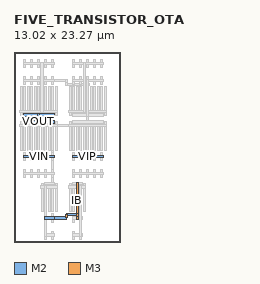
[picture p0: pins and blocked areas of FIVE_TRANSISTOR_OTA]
MACRO FIVE_TRANSISTOR_OTA
  ORIGIN 0 0 ;
  FOREIGN FIVE_TRANSISTOR_OTA 0 0 ;
  SIZE 13.02 BY 23.27 ;
  PIN IB
    DIRECTION INOUT ;
    USE SIGNAL ;
    PORT 
      LAYER M2 ;
        RECT 3.7 2.8 4.9 3.08 ;
      LAYER M3 ;
        RECT 7.6 2.78 7.88 7.3 ;
      LAYER M2 ;
        RECT 4.73 2.8 6.45 3.08 ;
      LAYER M3 ;
        RECT 6.31 2.94 6.59 3.36 ;
      LAYER M2 ;
        RECT 6.45 3.22 7.74 3.5 ;
      LAYER M3 ;
        RECT 7.6 3.175 7.88 3.545 ;
    END
  END IB
  PIN VOUT
    DIRECTION INOUT ;
    USE SIGNAL ;
    PORT 
      LAYER M2 ;
        RECT 1.12 14.56 4.9 14.84 ;
      LAYER M2 ;
        RECT 1.12 15.4 4.9 15.68 ;
      LAYER M2 ;
        RECT 2.85 14.56 3.17 14.84 ;
      LAYER M3 ;
        RECT 2.87 14.7 3.15 15.54 ;
      LAYER M2 ;
        RECT 2.85 15.4 3.17 15.68 ;
    END
  END VOUT
  PIN VIP
    DIRECTION INOUT ;
    USE SIGNAL ;
    PORT 
      LAYER M2 ;
        RECT 7.14 10.36 10.92 10.64 ;
    END
  END VIP
  PIN VIN
    DIRECTION INOUT ;
    USE SIGNAL ;
    PORT 
      LAYER M2 ;
        RECT 1.12 10.36 4.9 10.64 ;
    END
  END VIN
  OBS 
  LAYER M2 ;
        RECT 1.12 19.6 4.9 19.88 ;
  LAYER M3 ;
        RECT 8.89 15.38 9.17 19.9 ;
  LAYER M2 ;
        RECT 7.14 14.56 10.92 14.84 ;
  LAYER M2 ;
        RECT 4.73 19.6 6.45 19.88 ;
  LAYER M3 ;
        RECT 6.31 19.32 6.59 19.74 ;
  LAYER M2 ;
        RECT 6.45 19.18 9.03 19.46 ;
  LAYER M3 ;
        RECT 8.89 19.135 9.17 19.505 ;
  LAYER M3 ;
        RECT 8.89 14.7 9.17 15.54 ;
  LAYER M2 ;
        RECT 8.87 14.56 9.19 14.84 ;
  LAYER M2 ;
        RECT 6.29 19.18 6.61 19.46 ;
  LAYER M3 ;
        RECT 6.31 19.16 6.59 19.48 ;
  LAYER M2 ;
        RECT 6.29 19.6 6.61 19.88 ;
  LAYER M3 ;
        RECT 6.31 19.58 6.59 19.9 ;
  LAYER M2 ;
        RECT 8.87 19.18 9.19 19.46 ;
  LAYER M3 ;
        RECT 8.89 19.16 9.17 19.48 ;
  LAYER M2 ;
        RECT 6.29 19.18 6.61 19.46 ;
  LAYER M3 ;
        RECT 6.31 19.16 6.59 19.48 ;
  LAYER M2 ;
        RECT 6.29 19.6 6.61 19.88 ;
  LAYER M3 ;
        RECT 6.31 19.58 6.59 19.9 ;
  LAYER M2 ;
        RECT 8.87 19.18 9.19 19.46 ;
  LAYER M3 ;
        RECT 8.89 19.16 9.17 19.48 ;
  LAYER M2 ;
        RECT 6.29 19.18 6.61 19.46 ;
  LAYER M3 ;
        RECT 6.31 19.16 6.59 19.48 ;
  LAYER M2 ;
        RECT 6.29 19.6 6.61 19.88 ;
  LAYER M3 ;
        RECT 6.31 19.58 6.59 19.9 ;
  LAYER M2 ;
        RECT 8.87 14.56 9.19 14.84 ;
  LAYER M3 ;
        RECT 8.89 14.54 9.17 14.86 ;
  LAYER M2 ;
        RECT 8.87 19.18 9.19 19.46 ;
  LAYER M3 ;
        RECT 8.89 19.16 9.17 19.48 ;
  LAYER M2 ;
        RECT 6.29 19.18 6.61 19.46 ;
  LAYER M3 ;
        RECT 6.31 19.16 6.59 19.48 ;
  LAYER M2 ;
        RECT 6.29 19.6 6.61 19.88 ;
  LAYER M3 ;
        RECT 6.31 19.58 6.59 19.9 ;
  LAYER M2 ;
        RECT 8.87 14.56 9.19 14.84 ;
  LAYER M3 ;
        RECT 8.89 14.54 9.17 14.86 ;
  LAYER M2 ;
        RECT 8.87 19.18 9.19 19.46 ;
  LAYER M3 ;
        RECT 8.89 19.16 9.17 19.48 ;
  LAYER M2 ;
        RECT 3.7 7 4.9 7.28 ;
  LAYER M2 ;
        RECT 0.69 14.14 5.33 14.42 ;
  LAYER M2 ;
        RECT 6.71 14.14 11.35 14.42 ;
  LAYER M2 ;
        RECT 4.57 7 4.89 7.28 ;
  LAYER M3 ;
        RECT 4.59 7.14 4.87 14.28 ;
  LAYER M2 ;
        RECT 4.57 14.14 4.89 14.42 ;
  LAYER M2 ;
        RECT 5.16 14.14 6.88 14.42 ;
  LAYER M2 ;
        RECT 4.57 7 4.89 7.28 ;
  LAYER M3 ;
        RECT 4.59 6.98 4.87 7.3 ;
  LAYER M2 ;
        RECT 4.57 14.14 4.89 14.42 ;
  LAYER M3 ;
        RECT 4.59 14.12 4.87 14.44 ;
  LAYER M2 ;
        RECT 4.57 7 4.89 7.28 ;
  LAYER M3 ;
        RECT 4.59 6.98 4.87 7.3 ;
  LAYER M2 ;
        RECT 4.57 14.14 4.89 14.42 ;
  LAYER M3 ;
        RECT 4.59 14.12 4.87 14.44 ;
  LAYER M2 ;
        RECT 4.57 7 4.89 7.28 ;
  LAYER M3 ;
        RECT 4.59 6.98 4.87 7.3 ;
  LAYER M2 ;
        RECT 4.57 14.14 4.89 14.42 ;
  LAYER M3 ;
        RECT 4.59 14.12 4.87 14.44 ;
  LAYER M2 ;
        RECT 4.57 7 4.89 7.28 ;
  LAYER M3 ;
        RECT 4.59 6.98 4.87 7.3 ;
  LAYER M2 ;
        RECT 4.57 14.14 4.89 14.42 ;
  LAYER M3 ;
        RECT 4.59 14.12 4.87 14.44 ;
  LAYER M1 ;
        RECT 7.185 3.695 7.435 7.225 ;
  LAYER M1 ;
        RECT 7.185 2.435 7.435 3.445 ;
  LAYER M1 ;
        RECT 7.185 0.335 7.435 1.345 ;
  LAYER M1 ;
        RECT 6.755 3.695 7.005 7.225 ;
  LAYER M1 ;
        RECT 7.615 3.695 7.865 7.225 ;
  LAYER M1 ;
        RECT 8.045 3.695 8.295 7.225 ;
  LAYER M1 ;
        RECT 8.045 2.435 8.295 3.445 ;
  LAYER M1 ;
        RECT 8.045 0.335 8.295 1.345 ;
  LAYER M1 ;
        RECT 8.475 3.695 8.725 7.225 ;
  LAYER M2 ;
        RECT 7.14 2.8 8.34 3.08 ;
  LAYER M2 ;
        RECT 7.14 7 8.34 7.28 ;
  LAYER M2 ;
        RECT 7.14 0.7 8.34 0.98 ;
  LAYER M2 ;
        RECT 6.71 6.58 8.77 6.86 ;
  LAYER M3 ;
        RECT 7.6 2.78 7.88 7.3 ;
  LAYER M3 ;
        RECT 8.03 0.68 8.31 6.88 ;
  LAYER M1 ;
        RECT 10.625 15.455 10.875 18.985 ;
  LAYER M1 ;
        RECT 10.625 19.235 10.875 20.245 ;
  LAYER M1 ;
        RECT 10.625 21.335 10.875 22.345 ;
  LAYER M1 ;
        RECT 11.055 15.455 11.305 18.985 ;
  LAYER M1 ;
        RECT 10.195 15.455 10.445 18.985 ;
  LAYER M1 ;
        RECT 9.765 15.455 10.015 18.985 ;
  LAYER M1 ;
        RECT 9.765 19.235 10.015 20.245 ;
  LAYER M1 ;
        RECT 9.765 21.335 10.015 22.345 ;
  LAYER M1 ;
        RECT 9.335 15.455 9.585 18.985 ;
  LAYER M1 ;
        RECT 8.905 15.455 9.155 18.985 ;
  LAYER M1 ;
        RECT 8.905 19.235 9.155 20.245 ;
  LAYER M1 ;
        RECT 8.905 21.335 9.155 22.345 ;
  LAYER M1 ;
        RECT 8.475 15.455 8.725 18.985 ;
  LAYER M1 ;
        RECT 8.045 15.455 8.295 18.985 ;
  LAYER M1 ;
        RECT 8.045 19.235 8.295 20.245 ;
  LAYER M1 ;
        RECT 8.045 21.335 8.295 22.345 ;
  LAYER M1 ;
        RECT 7.615 15.455 7.865 18.985 ;
  LAYER M1 ;
        RECT 7.185 15.455 7.435 18.985 ;
  LAYER M1 ;
        RECT 7.185 19.235 7.435 20.245 ;
  LAYER M1 ;
        RECT 7.185 21.335 7.435 22.345 ;
  LAYER M1 ;
        RECT 6.755 15.455 7.005 18.985 ;
  LAYER M2 ;
        RECT 7.14 19.6 10.92 19.88 ;
  LAYER M2 ;
        RECT 7.14 15.4 10.92 15.68 ;
  LAYER M2 ;
        RECT 7.14 21.7 10.92 21.98 ;
  LAYER M2 ;
        RECT 6.71 15.82 11.35 16.1 ;
  LAYER M3 ;
        RECT 8.89 15.38 9.17 19.9 ;
  LAYER M3 ;
        RECT 8.46 15.8 8.74 22 ;
  LAYER M1 ;
        RECT 4.605 3.695 4.855 7.225 ;
  LAYER M1 ;
        RECT 4.605 2.435 4.855 3.445 ;
  LAYER M1 ;
        RECT 4.605 0.335 4.855 1.345 ;
  LAYER M1 ;
        RECT 5.035 3.695 5.285 7.225 ;
  LAYER M1 ;
        RECT 4.175 3.695 4.425 7.225 ;
  LAYER M1 ;
        RECT 3.745 3.695 3.995 7.225 ;
  LAYER M1 ;
        RECT 3.745 2.435 3.995 3.445 ;
  LAYER M1 ;
        RECT 3.745 0.335 3.995 1.345 ;
  LAYER M1 ;
        RECT 3.315 3.695 3.565 7.225 ;
  LAYER M2 ;
        RECT 3.7 0.7 4.9 0.98 ;
  LAYER M2 ;
        RECT 3.27 6.58 5.33 6.86 ;
  LAYER M2 ;
        RECT 3.7 7 4.9 7.28 ;
  LAYER M2 ;
        RECT 3.7 2.8 4.9 3.08 ;
  LAYER M3 ;
        RECT 3.73 0.68 4.01 6.88 ;
  LAYER M1 ;
        RECT 1.165 15.455 1.415 18.985 ;
  LAYER M1 ;
        RECT 1.165 19.235 1.415 20.245 ;
  LAYER M1 ;
        RECT 1.165 21.335 1.415 22.345 ;
  LAYER M1 ;
        RECT 0.735 15.455 0.985 18.985 ;
  LAYER M1 ;
        RECT 1.595 15.455 1.845 18.985 ;
  LAYER M1 ;
        RECT 2.025 15.455 2.275 18.985 ;
  LAYER M1 ;
        RECT 2.025 19.235 2.275 20.245 ;
  LAYER M1 ;
        RECT 2.025 21.335 2.275 22.345 ;
  LAYER M1 ;
        RECT 2.455 15.455 2.705 18.985 ;
  LAYER M1 ;
        RECT 2.885 15.455 3.135 18.985 ;
  LAYER M1 ;
        RECT 2.885 19.235 3.135 20.245 ;
  LAYER M1 ;
        RECT 2.885 21.335 3.135 22.345 ;
  LAYER M1 ;
        RECT 3.315 15.455 3.565 18.985 ;
  LAYER M1 ;
        RECT 3.745 15.455 3.995 18.985 ;
  LAYER M1 ;
        RECT 3.745 19.235 3.995 20.245 ;
  LAYER M1 ;
        RECT 3.745 21.335 3.995 22.345 ;
  LAYER M1 ;
        RECT 4.175 15.455 4.425 18.985 ;
  LAYER M1 ;
        RECT 4.605 15.455 4.855 18.985 ;
  LAYER M1 ;
        RECT 4.605 19.235 4.855 20.245 ;
  LAYER M1 ;
        RECT 4.605 21.335 4.855 22.345 ;
  LAYER M1 ;
        RECT 5.035 15.455 5.285 18.985 ;
  LAYER M2 ;
        RECT 1.12 21.7 4.9 21.98 ;
  LAYER M2 ;
        RECT 0.69 15.82 5.33 16.1 ;
  LAYER M2 ;
        RECT 1.12 15.4 4.9 15.68 ;
  LAYER M2 ;
        RECT 1.12 19.6 4.9 19.88 ;
  LAYER M3 ;
        RECT 3.3 15.8 3.58 22 ;
  LAYER M1 ;
        RECT 10.625 11.255 10.875 14.785 ;
  LAYER M1 ;
        RECT 10.625 9.995 10.875 11.005 ;
  LAYER M1 ;
        RECT 10.625 7.895 10.875 8.905 ;
  LAYER M1 ;
        RECT 11.055 11.255 11.305 14.785 ;
  LAYER M1 ;
        RECT 10.195 11.255 10.445 14.785 ;
  LAYER M1 ;
        RECT 9.765 11.255 10.015 14.785 ;
  LAYER M1 ;
        RECT 9.765 9.995 10.015 11.005 ;
  LAYER M1 ;
        RECT 9.765 7.895 10.015 8.905 ;
  LAYER M1 ;
        RECT 9.335 11.255 9.585 14.785 ;
  LAYER M1 ;
        RECT 8.905 11.255 9.155 14.785 ;
  LAYER M1 ;
        RECT 8.905 9.995 9.155 11.005 ;
  LAYER M1 ;
        RECT 8.905 7.895 9.155 8.905 ;
  LAYER M1 ;
        RECT 8.475 11.255 8.725 14.785 ;
  LAYER M1 ;
        RECT 8.045 11.255 8.295 14.785 ;
  LAYER M1 ;
        RECT 8.045 9.995 8.295 11.005 ;
  LAYER M1 ;
        RECT 8.045 7.895 8.295 8.905 ;
  LAYER M1 ;
        RECT 7.615 11.255 7.865 14.785 ;
  LAYER M1 ;
        RECT 7.185 11.255 7.435 14.785 ;
  LAYER M1 ;
        RECT 7.185 9.995 7.435 11.005 ;
  LAYER M1 ;
        RECT 7.185 7.895 7.435 8.905 ;
  LAYER M1 ;
        RECT 6.755 11.255 7.005 14.785 ;
  LAYER M2 ;
        RECT 7.14 8.26 10.92 8.54 ;
  LAYER M2 ;
        RECT 7.14 14.56 10.92 14.84 ;
  LAYER M2 ;
        RECT 7.14 10.36 10.92 10.64 ;
  LAYER M2 ;
        RECT 6.71 14.14 11.35 14.42 ;
  LAYER M1 ;
        RECT 1.165 11.255 1.415 14.785 ;
  LAYER M1 ;
        RECT 1.165 9.995 1.415 11.005 ;
  LAYER M1 ;
        RECT 1.165 7.895 1.415 8.905 ;
  LAYER M1 ;
        RECT 0.735 11.255 0.985 14.785 ;
  LAYER M1 ;
        RECT 1.595 11.255 1.845 14.785 ;
  LAYER M1 ;
        RECT 2.025 11.255 2.275 14.785 ;
  LAYER M1 ;
        RECT 2.025 9.995 2.275 11.005 ;
  LAYER M1 ;
        RECT 2.025 7.895 2.275 8.905 ;
  LAYER M1 ;
        RECT 2.455 11.255 2.705 14.785 ;
  LAYER M1 ;
        RECT 2.885 11.255 3.135 14.785 ;
  LAYER M1 ;
        RECT 2.885 9.995 3.135 11.005 ;
  LAYER M1 ;
        RECT 2.885 7.895 3.135 8.905 ;
  LAYER M1 ;
        RECT 3.315 11.255 3.565 14.785 ;
  LAYER M1 ;
        RECT 3.745 11.255 3.995 14.785 ;
  LAYER M1 ;
        RECT 3.745 9.995 3.995 11.005 ;
  LAYER M1 ;
        RECT 3.745 7.895 3.995 8.905 ;
  LAYER M1 ;
        RECT 4.175 11.255 4.425 14.785 ;
  LAYER M1 ;
        RECT 4.605 11.255 4.855 14.785 ;
  LAYER M1 ;
        RECT 4.605 9.995 4.855 11.005 ;
  LAYER M1 ;
        RECT 4.605 7.895 4.855 8.905 ;
  LAYER M1 ;
        RECT 5.035 11.255 5.285 14.785 ;
  LAYER M2 ;
        RECT 1.12 8.26 4.9 8.54 ;
  LAYER M2 ;
        RECT 1.12 14.56 4.9 14.84 ;
  LAYER M2 ;
        RECT 1.12 10.36 4.9 10.64 ;
  LAYER M2 ;
        RECT 0.69 14.14 5.33 14.42 ;
  END 
END FIVE_TRANSISTOR_OTA
